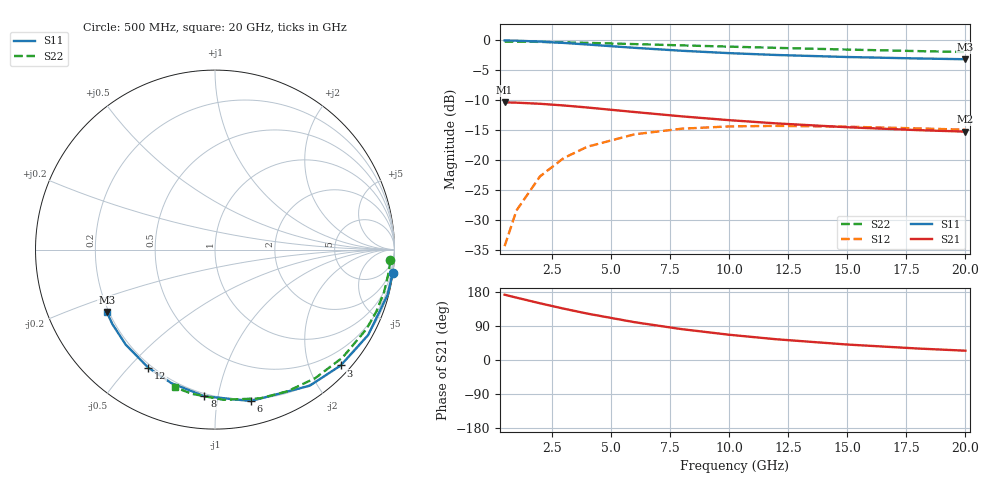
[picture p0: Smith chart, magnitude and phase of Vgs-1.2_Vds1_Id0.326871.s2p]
# Hz S RI R 50
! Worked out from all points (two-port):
!   12 points, 500 MHz to 20 GHz, reference 50 ohm
!   highest |S21| = -10.34 dB at 500 MHz (marker M1); lowest = -15.2 dB at 20 GHz (marker M2)
!   |S21| within 3 dB of the highest: start of sweep to 10.11 GHz
!   lowest |S11| = -3.1 dB at 20 GHz (marker M3), VSWR 5.58, Z = 9.58 - j12.9 ohm
!   |S11| at or under -10 dB: nowhere
!   |S22| runs from -1.9 to -0.2 dB; largest |S21 - S12| = 0.3
!   S11 on the Smith chart (normalised r, x): 500 MHz: 0, -15; 3 GHz: 0.18, -2.55; 6 GHz: 0.18, -1.25; 8 GHz: 0.18, -0.91; 12 GHz: 0.19, -0.57; 20 GHz: 0.19, -0.26
5e8  0.9901 -0.1292  -0.3013 0.0409  0.00185 0.0191  0.9763 -0.0606
1e9  0.9609 -0.2541  -0.2915 0.0803  0.00727 0.0374  0.9692 -0.1207
2e9  0.8532 -0.476  -0.2553 0.1496  0.0271 0.0683  0.942 -0.2367
3e9  0.7001 -0.6456  -0.2044 0.2007  0.0547 0.0888  0.8995 -0.3442
4e9  0.5277 -0.7584  -0.1477 0.2324  0.0847 0.0982  0.8447 -0.4416
6e9  0.1992 -0.8436  -0.0429 0.2489  0.1372 0.0912  0.7107 -0.6013
8e9  -0.0587 -0.817  0.0348 0.2297  0.171 0.0662  0.5587 -0.7162
1e10  -0.2431 -0.7439  0.0856 0.1983  0.1879 0.0374  0.4028 -0.7898
1.2e10  -0.3722 -0.6574  0.1172 0.1658  0.1933 0.0112  0.2516 -0.8287
1.5e10  -0.4971 -0.5298  0.1427 0.1232  0.1895 -0.0198  0.0458 -0.837
1.8e10  -0.5714 -0.4156  0.1541 0.0899  0.1798 -0.0413  -0.1279 -0.8036
2e10  -0.6032 -0.3474  0.1576 0.072  0.1724 -0.0517  -0.2255 -0.7666
